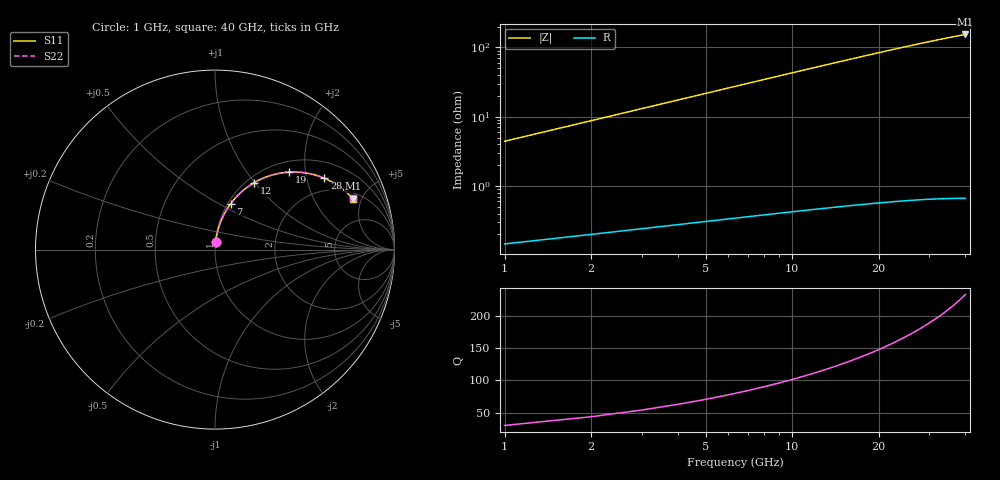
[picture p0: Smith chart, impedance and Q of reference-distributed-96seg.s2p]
! circuitRF wBond ? one port per TERMINAL, all referenced to the ground plane at z = 0, which is this file's common reference node.
! 1 array(s), 1 wire(s). Reference impedance 50 ohm, uniform and real.
! Port[1] = G1.i
! Port[2] = G1.o
! Model: distributed (MoM), 96 segments per wire, 97 current unknowns.
! Includes the wires' capacitance to the reference plane and between arrays.
! Medium: air (er = 1) ? no overmold.
# GHz S RI R 50
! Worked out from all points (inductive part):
!   40 points, 1 GHz to 40 GHz, reference 50 ohm
!   read as one part in series: L = 698 pH near 1 GHz
!   highest Q = 232 at 40 GHz (marker M1), where L = 613 pH
!   S11 on the Smith chart (normalised r, x): 1 GHz: 1.00, +0.08; 7 GHz: 1.03, +0.57; 12 GHz: 1.08, +0.99; 19 GHz: 1.21, +1.62; 28 GHz: 1.52, +2.56; 40 GHz: 2.46, +4.24
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1  0.0034 0.041  0.9966 -0.047  0.9966 -0.047  0.00339 0.041
2  0.00957 0.0808  0.9904 -0.0927  0.9904 -0.0927  0.00955 0.0808
3  0.0191 0.1193  0.9807 -0.1373  0.9807 -0.1373  0.0191 0.1194
4  0.032 0.1565  0.9678 -0.1804  0.9678 -0.1804  0.0319 0.1565
5  0.0479 0.1919  0.9518 -0.2218  0.9518 -0.2218  0.0477 0.1919
6  0.0665 0.2252  0.933 -0.2611  0.933 -0.2611  0.0663 0.2252
7  0.0875 0.2561  0.9117 -0.2981  0.9117 -0.2981  0.0873 0.2562
8  0.1106 0.2846  0.8884 -0.3326  0.8884 -0.3326  0.1103 0.2847
9  0.1354 0.3105  0.8633 -0.3645  0.8633 -0.3645  0.1351 0.3107
10  0.1616 0.3337  0.8368 -0.3937  0.8368 -0.3937  0.1612 0.3339
12  0.2167 0.3721  0.7809 -0.4442  0.7809 -0.4442  0.2162 0.3723
14  0.2735 0.4001  0.7232 -0.4843  0.7232 -0.4843  0.2729 0.4005
16  0.3301 0.4186  0.6656 -0.5151  0.6656 -0.5151  0.3293 0.4192
19  0.4113 0.4312  0.5825 -0.5462  0.5825 -0.5462  0.4104 0.4321
21  0.4618 0.4314  0.5306 -0.5587  0.5306 -0.5587  0.4608 0.4325
24  0.5307 0.4221  0.4592 -0.5681  0.4592 -0.5681  0.5296 0.4235
27  0.5913 0.4043  0.3958 -0.5693  0.3958 -0.5693  0.59 0.4062
28  0.6096 0.397  0.3764 -0.5684  0.3764 -0.5684  0.6083 0.399
31  0.6594 0.3722  0.3232 -0.5627  0.3232 -0.5627  0.658 0.3746
34  0.702 0.3441  0.2767 -0.5542  0.2767 -0.5542  0.7006 0.347
37  0.7382 0.3141  0.2361 -0.5439  0.2361 -0.5439  0.7367 0.3174
40  0.7688 0.2831  0.2006 -0.533  0.2006 -0.533  0.7674 0.2869
